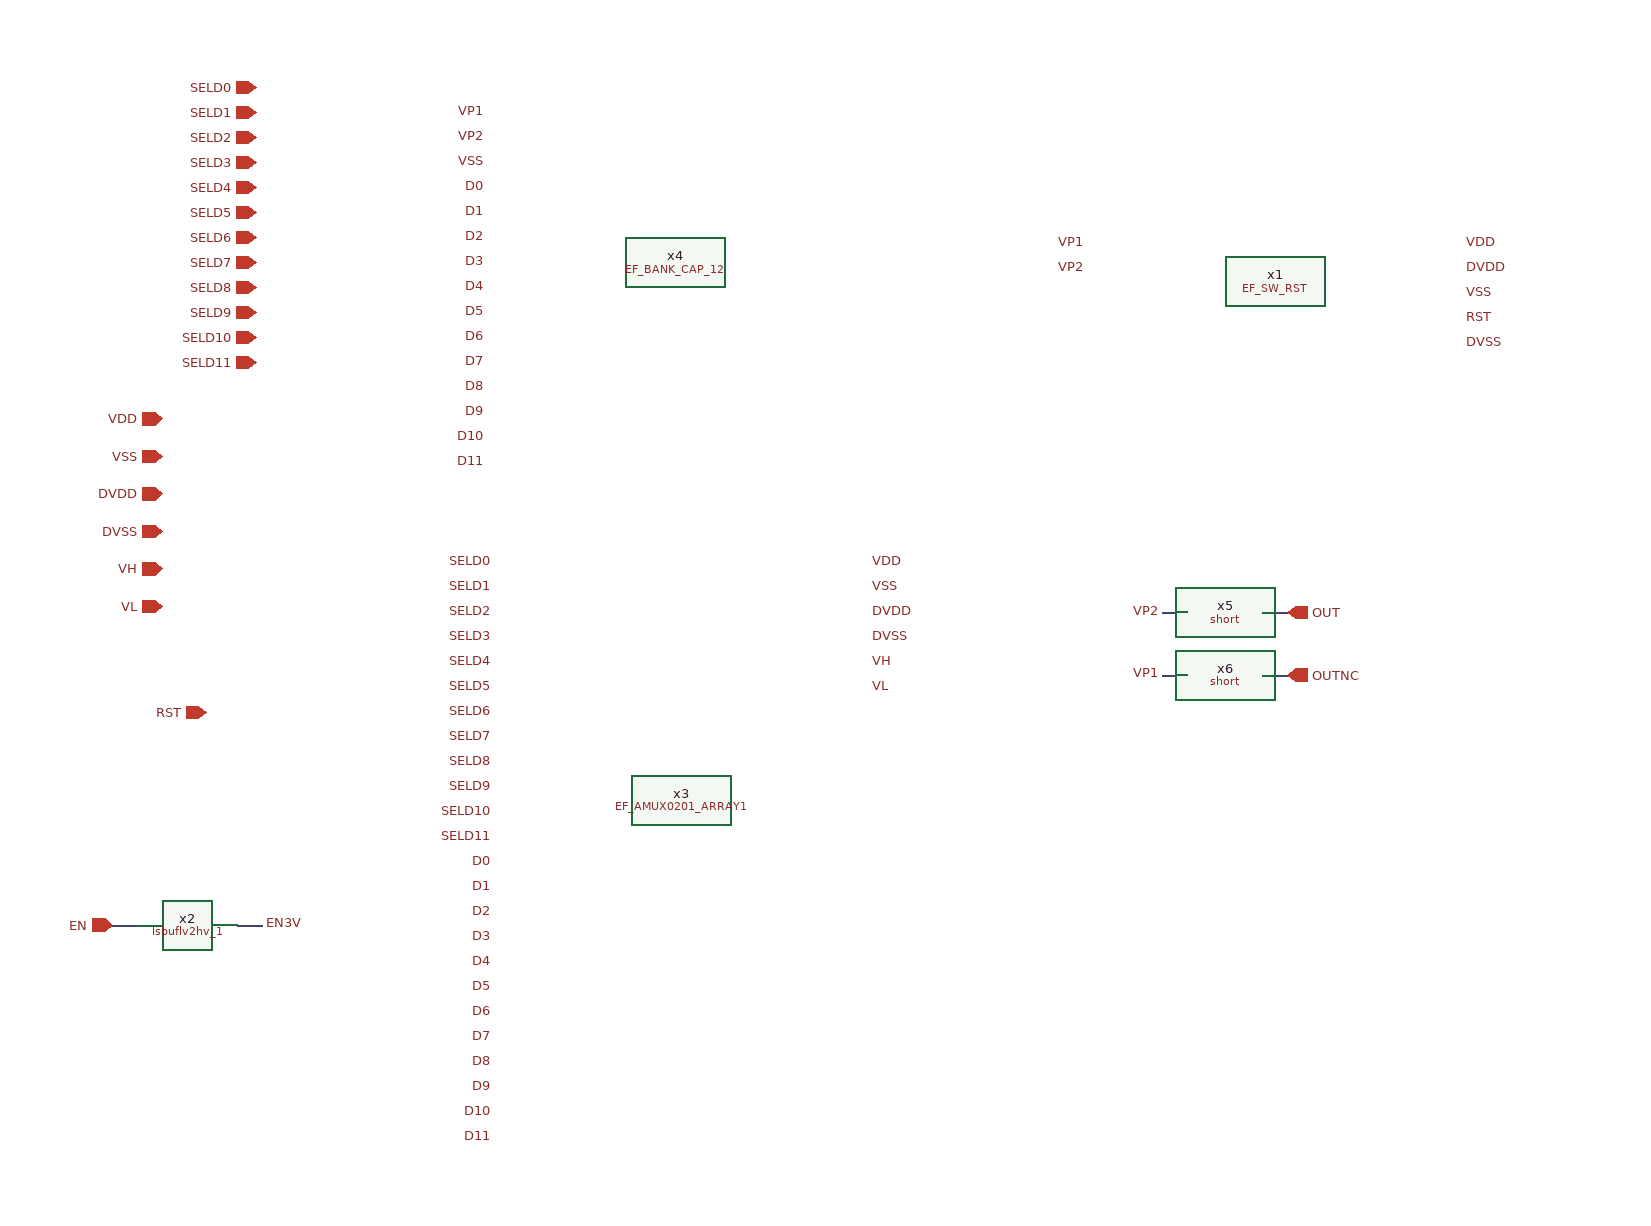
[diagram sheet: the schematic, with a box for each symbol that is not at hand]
v {xschem version=3.4.5 file_version=1.2
}
G {}
K {}
V {}
S {}
E {}
N -610 -850 -590 -850 {
lab=EN}
N -510 -850 -490 -850 {
lab=EN3V}
N 310 -1100 330 -1100 {
lab=OUT}
N 230 -1100 250 -1100 {
lab=OUT}
N 310 -1050 330 -1050 {
lab=OUTNC}
N 230 -1050 250 -1050 {
lab=OUTNC}
C {devices/lab_pin.sym} -310 -1480 0 0 {name=p2 sig_type=std_logic lab=VP2}
C {devices/lab_pin.sym} -310 -1440 0 0 {name=p3 sig_type=std_logic lab=D0}
C {devices/lab_pin.sym} -310 -1360 0 0 {name=p4 sig_type=std_logic lab=D4}
C {devices/lab_pin.sym} -310 -1280 0 0 {name=p5 sig_type=std_logic lab=D8}
C {devices/lab_pin.sym} -310 -1260 0 0 {name=p7 sig_type=std_logic lab=D9}
C {devices/lab_pin.sym} -310 -1340 0 0 {name=p9 sig_type=std_logic lab=D5}
C {devices/lab_pin.sym} -310 -1420 0 0 {name=p10 sig_type=std_logic lab=D1}
C {devices/lab_pin.sym} -310 -1400 0 0 {name=p47 sig_type=std_logic lab=D2}
C {devices/lab_pin.sym} -310 -1320 0 0 {name=p48 sig_type=std_logic lab=D6}
C {devices/lab_pin.sym} -310 -1460 0 0 {name=p71 sig_type=std_logic lab=VSS}
C {devices/lab_pin.sym} -310 -1300 0 0 {name=p72 sig_type=std_logic lab=D7}
C {devices/lab_pin.sym} -310 -1380 0 0 {name=p81 sig_type=std_logic lab=D3}
C {devices/lab_pin.sym} -310 -1500 0 0 {name=p1 sig_type=std_logic lab=VP1}
C {devices/lab_pin.sym} -305 -1040 0 0 {name=p6 sig_type=std_logic lab=SELD5}
C {devices/lab_pin.sym} -305 -1060 0 0 {name=p8 sig_type=std_logic lab=SELD4}
C {devices/lab_pin.sym} -305 -1080 0 0 {name=p11 sig_type=std_logic lab=SELD3}
C {devices/lab_pin.sym} -305 -1020 0 0 {name=p12 sig_type=std_logic lab=SELD6}
C {devices/lab_pin.sym} -305 -1000 0 0 {name=p13 sig_type=std_logic lab=SELD7}
C {devices/lab_pin.sym} -305 -1100 0 0 {name=p14 sig_type=std_logic lab=SELD2}
C {devices/lab_pin.sym} -305 -980 0 0 {name=p15 sig_type=std_logic lab=SELD8}
C {devices/lab_pin.sym} -305 -1140 0 0 {name=p16 sig_type=std_logic lab=SELD0}
C {devices/lab_pin.sym} -305 -1120 0 0 {name=p17 sig_type=std_logic lab=SELD1}
C {devices/lab_pin.sym} -305 -960 0 0 {name=p18 sig_type=std_logic lab=SELD9}
C {devices/lab_pin.sym} -305 -900 0 0 {name=p19 sig_type=std_logic lab=D0}
C {devices/lab_pin.sym} -305 -880 0 0 {name=p20 sig_type=std_logic lab=D1}
C {devices/lab_pin.sym} -305 -860 0 0 {name=p21 sig_type=std_logic lab=D2}
C {devices/lab_pin.sym} -305 -840 0 0 {name=p22 sig_type=std_logic lab=D3}
C {devices/lab_pin.sym} -305 -820 0 0 {name=p23 sig_type=std_logic lab=D4}
C {devices/lab_pin.sym} -305 -800 0 0 {name=p24 sig_type=std_logic lab=D5}
C {devices/lab_pin.sym} -305 -780 0 0 {name=p25 sig_type=std_logic lab=D6}
C {devices/lab_pin.sym} -305 -760 0 0 {name=p26 sig_type=std_logic lab=D7}
C {devices/lab_pin.sym} -305 -740 0 0 {name=p27 sig_type=std_logic lab=D8}
C {devices/lab_pin.sym} -305 -720 0 0 {name=p28 sig_type=std_logic lab=D9}
C {devices/lab_pin.sym} -5 -1140 0 1 {name=p29 sig_type=std_logic lab=VDD}
C {devices/lab_pin.sym} -5 -1100 0 1 {name=p49 sig_type=std_logic lab=DVDD}
C {devices/lab_pin.sym} -5 -1080 0 1 {name=p54 sig_type=std_logic lab=DVSS}
C {devices/lab_pin.sym} -5 -1060 0 1 {name=p55 sig_type=std_logic lab=VH}
C {devices/lab_pin.sym} -5 -1040 0 1 {name=p56 sig_type=std_logic lab=VL}
C {devices/lab_pin.sym} 170 -1395 0 0 {name=p57 sig_type=std_logic lab=VP1}
C {devices/lab_pin.sym} 170 -1375 0 0 {name=p58 sig_type=std_logic lab=VP2}
C {devices/lab_pin.sym} 470 -1395 0 1 {name=p59 sig_type=std_logic lab=VDD}
C {devices/lab_pin.sym} 470 -1375 0 1 {name=p62 sig_type=std_logic lab=DVDD}
C {devices/lab_pin.sym} 470 -1355 0 1 {name=p63 sig_type=std_logic lab=VSS}
C {devices/lab_pin.sym} 470 -1335 0 1 {name=p64 sig_type=std_logic lab=RST}
C {EF_BANK_CAP_12.sym} -160 -1380 0 0 {name=x4}
C {EF_AMUX0201_ARRAY1.sym} -155 -950 0 0 {name=x3}
C {EF_SW_RST.sym} 320 -1365 0 0 {name=x1}
C {devices/ipin.sym} -495 -1520 0 0 {name=p61 lab=SELD0}
C {devices/ipin.sym} -495 -1500 0 0 {name=p30 lab=SELD1}
C {devices/ipin.sym} -495 -1480 0 0 {name=p31 lab=SELD2}
C {devices/ipin.sym} -495 -1460 0 0 {name=p32 lab=SELD3}
C {devices/ipin.sym} -495 -1440 0 0 {name=p65 lab=SELD4}
C {devices/ipin.sym} -495 -1420 0 0 {name=p66 lab=SELD5}
C {devices/ipin.sym} -495 -1400 0 0 {name=p67 lab=SELD6}
C {devices/ipin.sym} -495 -1380 0 0 {name=p68 lab=SELD7}
C {devices/ipin.sym} -495 -1360 0 0 {name=p69 lab=SELD8}
C {devices/ipin.sym} -495 -1340 0 0 {name=p70 lab=SELD9}
C {devices/iopin.sym} -570 -1255 0 0 {name=p33 lab=VDD}
C {devices/iopin.sym} -570 -1195 0 0 {name=p34 lab=DVDD}
C {devices/iopin.sym} -570 -1165 0 0 {name=p35 lab=DVSS}
C {devices/iopin.sym} -570 -1135 0 0 {name=p41 lab=VH}
C {devices/iopin.sym} -570 -1105 0 0 {name=p42 lab=VL}
C {devices/iopin.sym} -570 -1225 0 0 {name=p43 lab=VSS}
C {devices/ipin.sym} -535 -1020 0 0 {name=p46 lab=RST}
C {lsbuflv2hv_1.sym} -550 -850 0 0 {name=x2 LVPWR=DVDD VGND=DVSS VNB=DVSS VPB=VDD VPWR=VDD prefix=sky130_fd_sc_hvl__ }
C {devices/ipin.sym} -610 -850 0 0 {name=p38 lab=EN}
C {devices/lab_pin.sym} -490 -850 0 1 {name=p45 sig_type=std_logic lab=EN3V}
C {devices/lab_pin.sym} 470 -1315 0 1 {name=p36 sig_type=std_logic lab=DVSS}
C {devices/lab_pin.sym} -5 -1120 0 1 {name=p44 sig_type=std_logic lab=VSS}
C {devices/opin.sym} 330 -1100 0 0 {name=p39 lab=OUT}
C {devices/opin.sym} 330 -1050 0 0 {name=p40 lab=OUTNC}
C {devices/short.sym} 280 -1100 3 0 {name=x5 value=0.1}
C {devices/lab_pin.sym} 230 -1100 0 0 {name=p50 sig_type=std_logic lab=VP2}
C {devices/short.sym} 280 -1050 3 0 {name=x6 value=0.1}
C {devices/lab_pin.sym} 230 -1050 0 0 {name=p51 sig_type=std_logic lab=VP1}
C {devices/ipin.sym} -495 -1320 0 0 {name=p37 lab=SELD10}
C {devices/ipin.sym} -495 -1300 0 0 {name=p52 lab=SELD11}
C {devices/lab_pin.sym} -310 -1240 0 0 {name=p53 sig_type=std_logic lab=D10}
C {devices/lab_pin.sym} -310 -1220 0 0 {name=p60 sig_type=std_logic lab=D11}
C {devices/lab_pin.sym} -305 -940 0 0 {name=p73 sig_type=std_logic lab=SELD10}
C {devices/lab_pin.sym} -305 -920 0 0 {name=p74 sig_type=std_logic lab=SELD11}
C {devices/lab_pin.sym} -305 -700 0 0 {name=p75 sig_type=std_logic lab=D10}
C {devices/lab_pin.sym} -305 -680 0 0 {name=p76 sig_type=std_logic lab=D11}
